VERSION 5.7 ;
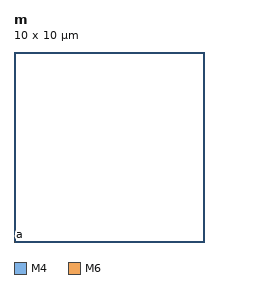
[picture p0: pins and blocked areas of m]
MACRO m
 CLASS BLOCK ;
 SIZE 10 BY 10 ;
 SYMMETRY X Y ;
 PIN a
 USE SIGNAL ;
 PORT
 LAYER M4 ;
 RECT 0.000 0.000 0.024 0.024 ;
 END
 END a
 PIN b
 USE SIGNAL ;
 PORT
 LAYER M6 ;
 RECT 0.000 0.000 0.032 0.028 ;
 END
 END b
END m
END LIBRARY
